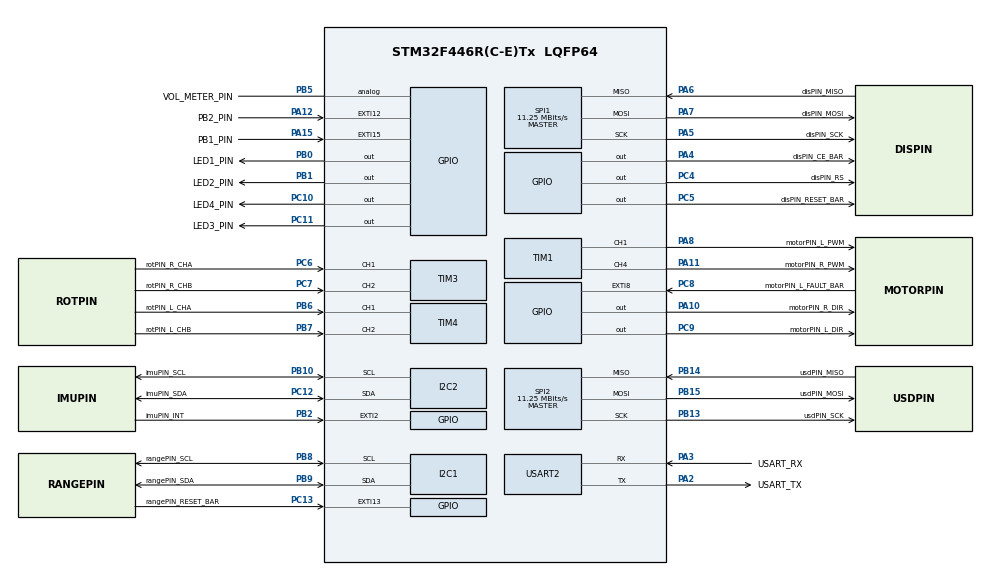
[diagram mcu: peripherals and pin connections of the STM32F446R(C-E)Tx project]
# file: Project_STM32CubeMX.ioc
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FREERTOS.Tasks01=defaultTask,0,128,StartDefaultTask
Mcu.Family=STM32F4
Mcu.Name=STM32F446R(C-E)Tx
Mcu.Package=LQFP64
NVIC.PriorityGroup=NVIC_PRIORITYGROUP_4
PA10.GPIO_Label=motorPIN_R_DIR
PA10.Signal=GPIO_Output
PA11.GPIO_Label=motorPIN_R_PWM
PA11.Signal=S_TIM1_CH4
PA12.GPIO_Label=PB2_PIN
PA12.Signal=GPXTI12
PA13.GPIO_Label=TMS
PA13.Mode=Trace-Asynchronous_SW
PA13.Signal=SYS_JTMS-SWDIO
PA14.GPIO_Label=TCK
PA14.Mode=Trace-Asynchronous_SW
PA14.Signal=SYS_JTCK-SWCLK
PA15.GPIO_Label=PB1_PIN
PA15.Signal=GPXTI15
PA2.GPIO_Label=USART_TX
PA2.Mode=Asynchronous
PA2.Signal=USART2_TX
PA3.GPIO_Label=USART_RX
PA3.Mode=Asynchronous
PA3.Signal=USART2_RX
PA4.GPIO_Label=disPIN_CE_BAR
PA4.Signal=GPIO_Output
PA5.GPIO_Label=disPIN_SCK
PA5.Mode=Full_Duplex_Master
PA5.Signal=SPI1_SCK
PA6.GPIO_Label=disPIN_MISO
PA6.Mode=Full_Duplex_Master
PA6.Signal=SPI1_MISO
PA7.GPIO_Label=disPIN_MOSI
PA7.Mode=Full_Duplex_Master
PA7.Signal=SPI1_MOSI
PA8.GPIO_Label=motorPIN_L_PWM
PA8.Signal=S_TIM1_CH1
PA9.GPIO_Label=motorPIN_R_FAULT_BAR
PA9.Signal=S_TIM1_CH2
PB0.GPIO_Label=LED1_PIN
PB0.Signal=GPIO_Output
PB1.GPIO_Label=LED2_PIN
PB1.Signal=GPIO_Output
PB10.GPIO_Label=imuPIN_SCL
PB10.Mode=I2C
PB10.Signal=I2C2_SCL
PB12.GPIO_Label=usdPIN_SS_BAR
PB12.Signal=SPI2_NSS
PB13.GPIO_Label=usdPIN_SCK
PB13.Mode=Full_Duplex_Master
PB13.Signal=SPI2_SCK
PB14.GPIO_Label=usdPIN_MISO
PB14.Mode=Full_Duplex_Master
PB14.Signal=SPI2_MISO
PB15.GPIO_Label=usdPIN_MOSI
PB15.Mode=Full_Duplex_Master
PB15.Signal=SPI2_MOSI
PB2.GPIO_Label=imuPIN_INT
PB2.Signal=GPXTI2
PB3.GPIO_Label=SWO
PB3.Mode=Trace-Asynchronous_SW
PB3.Signal=SYS_JTDO-SWO
PB5.GPIO_Label=VOL_METER_PIN
PB5.Signal=GPIO_Analog
PB6.GPIO_Label=rotPIN_L_CHA
PB6.Signal=S_TIM4_CH1
PB7.GPIO_Label=rotPIN_L_CHB
PB7.Signal=S_TIM4_CH2
PB8.GPIO_Label=rangePIN_SCL
PB8.Mode=I2C
PB8.Signal=I2C1_SCL
PB9.GPIO_Label=rangePIN_SDA
PB9.Mode=I2C
PB9.Signal=I2C1_SDA
PC10.GPIO_Label=LED4_PIN
PC10.Signal=GPIO_Output
PC11.GPIO_Label=LED3_PIN
PC11.Signal=GPIO_Output
PC12.GPIO_Label=imuPIN_SDA
PC12.Mode=I2C
PC12.Signal=I2C2_SDA
PC13.GPIO_Label=rangePIN_RESET_BAR
PC13.GPIO_ModeDefaultEXTI=GPIO_MODE_EVT_RISING
PC13.Signal=GPXTI13
PC14-OSC32_IN.Signal=RCC_OSC32_IN
PC15-OSC32_OUT.Signal=RCC_OSC32_OUT
PC4.GPIO_Label=disPIN_RS
PC4.Signal=GPIO_Output
PC5.GPIO_Label=disPIN_RESET_BAR
PC5.Signal=GPIO_Output
PC6.GPIO_Label=rotPIN_R_CHA
PC6.Signal=S_TIM3_CH1
PC7.GPIO_Label=rotPIN_R_CHB
PC7.Signal=S_TIM3_CH2
PC8.GPIO_Label=motorPIN_L_FAULT_BAR
PC8.Signal=GPXTI8
PC9.GPIO_Label=motorPIN_L_DIR
PC9.Signal=GPIO_Output
PH0-OSC_IN.Signal=RCC_OSC_IN
PH1-OSC_OUT.Signal=RCC_OSC_OUT
ProjectManager.HeapSize=0x200
ProjectManager.StackSize=0x400
ProjectManager.TargetToolchain=TrueSTUDIO
RCC.AHBFreq_Value=90000000
RCC.APB1CLKDivider=RCC_HCLK_DIV4
RCC.APB1Freq_Value=22500000
RCC.APB1TimFreq_Value=45000000
RCC.APB2CLKDivider=RCC_HCLK_DIV4
RCC.APB2Freq_Value=22500000
RCC.APB2TimFreq_Value=45000000
RCC.CortexFreq_Value=90000000
RCC.FLatency-AdvancedSettings=FLASH_LATENCY_2
RCC.HCLKFreq_Value=90000000
RCC.HSE_VALUE=8000000
RCC.HSI_VALUE=16000000
RCC.LSE_VALUE=32768
RCC.PLLN=360
RCC.PLLP=RCC_PLLP_DIV4
RCC.PWREXT_OverDrive=PWREXT_OverDrive_ACTIVATED
RCC.PWR_Regulator_Voltage_Scale=PWR_REGULATOR_VOLTAGE_SCALE1
RCC.SYSCLKFreq_VALUE=90000000
RCC.SYSCLKSource=RCC_SYSCLKSOURCE_PLLCLK
RCC.USBFreq_Value=180000000
RCC.VCOOutputFreq_Value=360000000
SH.S_TIM1_CH1.0=TIM1_CH1,PWM Generation1 CH1
SH.S_TIM1_CH2.0=TIM1_CH2
SH.S_TIM1_CH4.0=TIM1_CH4,PWM Generation4 CH4
SH.S_TIM3_CH1.0=TIM3_CH1,Input_Capture1_from_TI1
SH.S_TIM3_CH2.0=TIM3_CH2,Input_Capture2_from_TI2
SH.S_TIM4_CH1.0=TIM4_CH1,Input_Capture1_from_TI1
SH.S_TIM4_CH2.0=TIM4_CH2,Input_Capture2_from_TI2
SPI1.CalculateBaudRate=11.25 MBits/s
SPI1.Mode=SPI_MODE_MASTER
SPI2.CalculateBaudRate=11.25 MBits/s
SPI2.Mode=SPI_MODE_MASTER
SPI2.VirtualNSS=VM_NSSHARD
TIM1.Channel-PWM\ Generation4\ CH4=TIM_CHANNEL_4
TIM3.Channel-Input_Capture2_from_TI2=TIM_CHANNEL_2
TIM4.Channel-Input_Capture2_from_TI2=TIM_CHANNEL_2
VP_FATFS_VS_Generic.Mode=User_defined
VP_FREERTOS_VS_ENABLE.Mode=Enabled
VP_TIM3_VS_ClockSourceINT.Mode=Internal
board=NUCLEO-F446RE

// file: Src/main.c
/**
  ******************************************************************************
  * File Name          : main.c
  * Description        : Main program body
  ******************************************************************************
  *
  * COPYRIGHT(c) 2016 STMicroelectronics
  *
  * Redistribution and use in source and binary forms, with or without modification,
  * are permitted provided that the following conditions are met:
  *   1. Redistributions of source code must retain the above copyright notice,
  *      this list of conditions and the following disclaimer.
  *   2. Redistributions in binary form must reproduce the above copyright notice,
  *      this list of conditions and the following disclaimer in the documentation
  *      and/or other materials provided with the distribution.
  *   3. Neither the name of STMicroelectronics nor the names of its contributors
  *      may be used to endorse or promote products derived from this software
  *      without specific prior written permission.
  *
  * THIS SOFTWARE IS PROVIDED BY THE COPYRIGHT HOLDERS AND CONTRIBUTORS "AS IS"
  * AND ANY EXPRESS OR IMPLIED WARRANTIES, INCLUDING, BUT NOT LIMITED TO, THE
  * IMPLIED WARRANTIES OF MERCHANTABILITY AND FITNESS FOR A PARTICULAR PURPOSE ARE
  * DISCLAIMED. IN NO EVENT SHALL THE COPYRIGHT HOLDER OR CONTRIBUTORS BE LIABLE
  * FOR ANY DIRECT, INDIRECT, INCIDENTAL, SPECIAL, EXEMPLARY, OR CONSEQUENTIAL
  * DAMAGES (INCLUDING, BUT NOT LIMITED TO, PROCUREMENT OF SUBSTITUTE GOODS OR
  * SERVICES; LOSS OF USE, DATA, OR PROFITS; OR BUSINESS INTERRUPTION) HOWEVER
  * CAUSED AND ON ANY THEORY OF LIABILITY, WHETHER IN CONTRACT, STRICT LIABILITY,
  * OR TORT (INCLUDING NEGLIGENCE OR OTHERWISE) ARISING IN ANY WAY OUT OF THE USE
  * OF THIS SOFTWARE, EVEN IF ADVISED OF THE POSSIBILITY OF SUCH DAMAGE.
  *
  ******************************************************************************
  */
#include "stm32f4xx_hal.h"
#include "cmsis_os.h"
#include "fatfs.h"

I2C_HandleTypeDef hi2c1;
I2C_HandleTypeDef hi2c2;

SPI_HandleTypeDef hspi1;
SPI_HandleTypeDef hspi2;

TIM_HandleTypeDef htim1;
TIM_HandleTypeDef htim3;
TIM_HandleTypeDef htim4;

UART_HandleTypeDef huart2;

osThreadId defaultTaskHandle;

/* USER CODE BEGIN PV */
/* Private variables ---------------------------------------------------------*/

/* USER CODE END PV */

void SystemClock_Config(void);
static void MX_GPIO_Init(void);
static void MX_I2C1_Init(void);
static void MX_I2C2_Init(void);
static void MX_SPI1_Init(void);
static void MX_SPI2_Init(void);
static void MX_TIM1_Init(void);
static void MX_TIM3_Init(void);
static void MX_TIM4_Init(void);
static void MX_USART2_UART_Init(void);
void StartDefaultTask(void const * argument);

void HAL_TIM_MspPostInit(TIM_HandleTypeDef *htim);

/* USER CODE BEGIN PFP */
/* Private function prototypes -----------------------------------------------*/

/* USER CODE END PFP */

int main(void)
{

  /* MCU Configuration----------------------------------------------------------*/

  /* Reset of all peripherals, Initializes the Flash interface and the Systick. */
  HAL_Init();

  /* Configure the system clock */
  SystemClock_Config();

  /* Initialize all configured peripherals */
  MX_GPIO_Init();
  MX_I2C1_Init();
  MX_I2C2_Init();
  MX_SPI1_Init();
  MX_SPI2_Init();
  MX_TIM1_Init();
  MX_TIM3_Init();
  MX_TIM4_Init();
  MX_USART2_UART_Init();

  /* Create the thread(s) */
  /* definition and creation of defaultTask */
  osThreadDef(defaultTask, StartDefaultTask, osPriorityNormal, 0, 128);
  defaultTaskHandle = osThreadCreate(osThread(defaultTask), NULL);

  /* Start scheduler */
  osKernelStart();

  /* We should never get here as control is now taken by the scheduler */

  /* Infinite loop */
  while (1)
  {

  }

}

/** System Clock Configuration
*/
void SystemClock_Config(void)
{

  RCC_OscInitTypeDef RCC_OscInitStruct;
  RCC_ClkInitTypeDef RCC_ClkInitStruct;

  __HAL_RCC_PWR_CLK_ENABLE();

  __HAL_PWR_VOLTAGESCALING_CONFIG(PWR_REGULATOR_VOLTAGE_SCALE1);

  RCC_OscInitStruct.OscillatorType = RCC_OSCILLATORTYPE_HSI;
  RCC_OscInitStruct.HSIState = RCC_HSI_ON;
  RCC_OscInitStruct.HSICalibrationValue = 16;
  RCC_OscInitStruct.PLL.PLLState = RCC_PLL_ON;
  RCC_OscInitStruct.PLL.PLLSource = RCC_PLLSOURCE_HSI;
  RCC_OscInitStruct.PLL.PLLM = 16;
  RCC_OscInitStruct.PLL.PLLN = 360;
  RCC_OscInitStruct.PLL.PLLP = RCC_PLLP_DIV2;
  RCC_OscInitStruct.PLL.PLLQ = 2;
  RCC_OscInitStruct.PLL.PLLR = 2;
  HAL_RCC_OscConfig(&RCC_OscInitStruct);

  HAL_PWREx_EnableOverDrive();

  RCC_ClkInitStruct.ClockType = RCC_CLOCKTYPE_HCLK|RCC_CLOCKTYPE_SYSCLK
                              |RCC_CLOCKTYPE_PCLK1|RCC_CLOCKTYPE_PCLK2;
  RCC_ClkInitStruct.SYSCLKSource = RCC_SYSCLKSOURCE_PLLCLK;
  RCC_ClkInitStruct.AHBCLKDivider = RCC_SYSCLK_DIV1;
  RCC_ClkInitStruct.APB1CLKDivider = RCC_HCLK_DIV4;
  RCC_ClkInitStruct.APB2CLKDivider = RCC_HCLK_DIV4;
  HAL_RCC_ClockConfig(&RCC_ClkInitStruct, FLASH_LATENCY_5);

  HAL_SYSTICK_Config(HAL_RCC_GetHCLKFreq()/1000);

  HAL_SYSTICK_CLKSourceConfig(SYSTICK_CLKSOURCE_HCLK);

  /* SysTick_IRQn interrupt configuration */
  HAL_NVIC_SetPriority(SysTick_IRQn, 15, 0);
}

/* I2C1 init function */
void MX_I2C1_Init(void)
{

  hi2c1.Instance = I2C1;
  hi2c1.Init.ClockSpeed = 100000;
  hi2c1.Init.DutyCycle = I2C_DUTYCYCLE_2;
  hi2c1.Init.OwnAddress1 = 0;
  hi2c1.Init.AddressingMode = I2C_ADDRESSINGMODE_7BIT;
  hi2c1.Init.DualAddressMode = I2C_DUALADDRESS_DISABLE;
  hi2c1.Init.OwnAddress2 = 0;
  hi2c1.Init.GeneralCallMode = I2C_GENERALCALL_DISABLE;
  hi2c1.Init.NoStretchMode = I2C_NOSTRETCH_DISABLE;
  HAL_I2C_Init(&hi2c1);

}

/* I2C2 init function */
void MX_I2C2_Init(void)
{

  hi2c2.Instance = I2C2;
  hi2c2.Init.ClockSpeed = 100000;
  hi2c2.Init.DutyCycle = I2C_DUTYCYCLE_2;
  hi2c2.Init.OwnAddress1 = 0;
  hi2c2.Init.AddressingMode = I2C_ADDRESSINGMODE_7BIT;
  hi2c2.Init.DualAddressMode = I2C_DUALADDRESS_DISABLE;
  hi2c2.Init.OwnAddress2 = 0;
  hi2c2.Init.GeneralCallMode = I2C_GENERALCALL_DISABLE;
  hi2c2.Init.NoStretchMode = I2C_NOSTRETCH_DISABLE;
  HAL_I2C_Init(&hi2c2);

}

/* SPI1 init function */
void MX_SPI1_Init(void)
{

  hspi1.Instance = SPI1;
  hspi1.Init.Mode = SPI_MODE_MASTER;
  hspi1.Init.Direction = SPI_DIRECTION_2LINES;
  hspi1.Init.DataSize = SPI_DATASIZE_8BIT;
  hspi1.Init.CLKPolarity = SPI_POLARITY_LOW;
  hspi1.Init.CLKPhase = SPI_PHASE_1EDGE;
  hspi1.Init.NSS = SPI_NSS_SOFT;
  hspi1.Init.BaudRatePrescaler = SPI_BAUDRATEPRESCALER_2;
  hspi1.Init.FirstBit = SPI_FIRSTBIT_MSB;
  hspi1.Init.TIMode = SPI_TIMODE_DISABLE;
  hspi1.Init.CRCCalculation = SPI_CRCCALCULATION_DISABLE;
  hspi1.Init.CRCPolynomial = 10;
  HAL_SPI_Init(&hspi1);

}

/* SPI2 init function */
void MX_SPI2_Init(void)
{

  hspi2.Instance = SPI2;
  hspi2.Init.Mode = SPI_MODE_MASTER;
  hspi2.Init.Direction = SPI_DIRECTION_2LINES;
  hspi2.Init.DataSize = SPI_DATASIZE_8BIT;
  hspi2.Init.CLKPolarity = SPI_POLARITY_LOW;
  hspi2.Init.CLKPhase = SPI_PHASE_1EDGE;
  hspi2.Init.NSS = SPI_NSS_SOFT;
  hspi2.Init.BaudRatePrescaler = SPI_BAUDRATEPRESCALER_2;
  hspi2.Init.FirstBit = SPI_FIRSTBIT_MSB;
  hspi2.Init.TIMode = SPI_TIMODE_DISABLE;
  hspi2.Init.CRCCalculation = SPI_CRCCALCULATION_DISABLE;
  hspi2.Init.CRCPolynomial = 10;
  HAL_SPI_Init(&hspi2);

}

/* TIM1 init function */
void MX_TIM1_Init(void)
{

  TIM_MasterConfigTypeDef sMasterConfig;
  TIM_BreakDeadTimeConfigTypeDef sBreakDeadTimeConfig;
  TIM_OC_InitTypeDef sConfigOC;

  htim1.Instance = TIM1;
  htim1.Init.Prescaler = 0;
  htim1.Init.CounterMode = TIM_COUNTERMODE_UP;
  htim1.Init.Period = 0;
  htim1.Init.ClockDivision = TIM_CLOCKDIVISION_DIV1;
  htim1.Init.RepetitionCounter = 0;
  HAL_TIM_PWM_Init(&htim1);

  sMasterConfig.MasterOutputTrigger = TIM_TRGO_RESET;
  sMasterConfig.MasterSlaveMode = TIM_MASTERSLAVEMODE_DISABLE;
  HAL_TIMEx_MasterConfigSynchronization(&htim1, &sMasterConfig);

  sBreakDeadTimeConfig.OffStateRunMode = TIM_OSSR_DISABLE;
  sBreakDeadTimeConfig.OffStateIDLEMode = TIM_OSSI_DISABLE;
  sBreakDeadTimeConfig.LockLevel = TIM_LOCKLEVEL_OFF;
  sBreakDeadTimeConfig.DeadTime = 0;
  sBreakDeadTimeConfig.BreakState = TIM_BREAK_DISABLE;
  sBreakDeadTimeConfig.BreakPolarity = TIM_BREAKPOLARITY_HIGH;
  sBreakDeadTimeConfig.AutomaticOutput = TIM_AUTOMATICOUTPUT_DISABLE;
  HAL_TIMEx_ConfigBreakDeadTime(&htim1, &sBreakDeadTimeConfig);

  sConfigOC.OCMode = TIM_OCMODE_PWM1;
  sConfigOC.Pulse = 0;
  sConfigOC.OCPolarity = TIM_OCPOLARITY_HIGH;
  sConfigOC.OCNPolarity = TIM_OCNPOLARITY_HIGH;
  sConfigOC.OCFastMode = TIM_OCFAST_DISABLE;
  sConfigOC.OCIdleState = TIM_OCIDLESTATE_RESET;
  sConfigOC.OCNIdleState = TIM_OCNIDLESTATE_RESET;
  HAL_TIM_PWM_ConfigChannel(&htim1, &sConfigOC, TIM_CHANNEL_1);

  HAL_TIM_PWM_ConfigChannel(&htim1, &sConfigOC, TIM_CHANNEL_4);

  HAL_TIM_MspPostInit(&htim1);

}

/* TIM3 init function */
void MX_TIM3_Init(void)
{

  TIM_ClockConfigTypeDef sClockSourceConfig;
  TIM_MasterConfigTypeDef sMasterConfig;
  TIM_IC_InitTypeDef sConfigIC;

  htim3.Instance = TIM3;
  htim3.Init.Prescaler = 0;
  htim3.Init.CounterMode = TIM_COUNTERMODE_UP;
  htim3.Init.Period = 0;
  htim3.Init.ClockDivision = TIM_CLOCKDIVISION_DIV1;
  HAL_TIM_Base_Init(&htim3);

  sClockSourceConfig.ClockSource = TIM_CLOCKSOURCE_INTERNAL;
  HAL_TIM_ConfigClockSource(&htim3, &sClockSourceConfig);

  HAL_TIM_IC_Init(&htim3);

  sMasterConfig.MasterOutputTrigger = TIM_TRGO_RESET;
  sMasterConfig.MasterSlaveMode = TIM_MASTERSLAVEMODE_DISABLE;
  HAL_TIMEx_MasterConfigSynchronization(&htim3, &sMasterConfig);

  sConfigIC.ICPolarity = TIM_INPUTCHANNELPOLARITY_RISING;
  sConfigIC.ICSelection = TIM_ICSELECTION_DIRECTTI;
  sConfigIC.ICPrescaler = TIM_ICPSC_DIV1;
  sConfigIC.ICFilter = 0;
  HAL_TIM_IC_ConfigChannel(&htim3, &sConfigIC, TIM_CHANNEL_1);

  HAL_TIM_IC_ConfigChannel(&htim3, &sConfigIC, TIM_CHANNEL_2);

}

/* TIM4 init function */
void MX_TIM4_Init(void)
{

  TIM_MasterConfigTypeDef sMasterConfig;
  TIM_IC_InitTypeDef sConfigIC;

  htim4.Instance = TIM4;
  htim4.Init.Prescaler = 0;
  htim4.Init.CounterMode = TIM_COUNTERMODE_UP;
  htim4.Init.Period = 0;
  htim4.Init.ClockDivision = TIM_CLOCKDIVISION_DIV1;
  HAL_TIM_IC_Init(&htim4);

  sMasterConfig.MasterOutputTrigger = TIM_TRGO_RESET;
  sMasterConfig.MasterSlaveMode = TIM_MASTERSLAVEMODE_DISABLE;
  HAL_TIMEx_MasterConfigSynchronization(&htim4, &sMasterConfig);

  sConfigIC.ICPolarity = TIM_INPUTCHANNELPOLARITY_RISING;
  sConfigIC.ICSelection = TIM_ICSELECTION_DIRECTTI;
  sConfigIC.ICPrescaler = TIM_ICPSC_DIV1;
  sConfigIC.ICFilter = 0;
  HAL_TIM_IC_ConfigChannel(&htim4, &sConfigIC, TIM_CHANNEL_1);

  HAL_TIM_IC_ConfigChannel(&htim4, &sConfigIC, TIM_CHANNEL_2);

}

/* USART2 init function */
void MX_USART2_UART_Init(void)
{

  huart2.Instance = USART2;
  huart2.Init.BaudRate = 115200;
  huart2.Init.WordLength = UART_WORDLENGTH_8B;
  huart2.Init.StopBits = UART_STOPBITS_1;
  huart2.Init.Parity = UART_PARITY_NONE;
  huart2.Init.Mode = UART_MODE_TX_RX;
  huart2.Init.HwFlowCtl = UART_HWCONTROL_NONE;
  huart2.Init.OverSampling = UART_OVERSAMPLING_16;
  HAL_UART_Init(&huart2);

}

/** Configure pins as
        * Analog
        * Input
        * Output
        * EVENT_OUT
        * EXTI
*/
void MX_GPIO_Init(void)
{

  GPIO_InitTypeDef GPIO_InitStruct;

  /* GPIO Ports Clock Enable */
  __HAL_RCC_GPIOC_CLK_ENABLE();
  __HAL_RCC_GPIOH_CLK_ENABLE();
  __HAL_RCC_GPIOA_CLK_ENABLE();
  __HAL_RCC_GPIOB_CLK_ENABLE();

  /*Configure GPIO pin : rangePIN_RESET_BAR_Pin */
  GPIO_InitStruct.Pin = rangePIN_RESET_BAR_Pin;
  GPIO_InitStruct.Mode = GPIO_MODE_EVT_RISING;
  GPIO_InitStruct.Pull = GPIO_NOPULL;
  HAL_GPIO_Init(rangePIN_RESET_BAR_GPIO_Port, &GPIO_InitStruct);

  /*Configure GPIO pins : disPIN_CE_BAR_Pin motorPIN_R_DIR_Pin */
  GPIO_InitStruct.Pin = disPIN_CE_BAR_Pin|motorPIN_R_DIR_Pin;
  GPIO_InitStruct.Mode = GPIO_MODE_OUTPUT_PP;
  GPIO_InitStruct.Pull = GPIO_NOPULL;
  GPIO_InitStruct.Speed = GPIO_SPEED_FREQ_LOW;
  HAL_GPIO_Init(GPIOA, &GPIO_InitStruct);

  /*Configure GPIO pins : disPIN_RS_Pin disPIN_RESET_BAR_Pin motorPIN_L_DIR_Pin LED4_PIN_Pin
                           LED3_PIN_Pin */
  GPIO_InitStruct.Pin = disPIN_RS_Pin|disPIN_RESET_BAR_Pin|motorPIN_L_DIR_Pin|LED4_PIN_Pin
                          |LED3_PIN_Pin;
  GPIO_InitStruct.Mode = GPIO_MODE_OUTPUT_PP;
  GPIO_InitStruct.Pull = GPIO_NOPULL;
  GPIO_InitStruct.Speed = GPIO_SPEED_FREQ_LOW;
  HAL_GPIO_Init(GPIOC, &GPIO_InitStruct);

  /*Configure GPIO pins : LED1_PIN_Pin LED2_PIN_Pin */
  GPIO_InitStruct.Pin = LED1_PIN_Pin|LED2_PIN_Pin;
  GPIO_InitStruct.Mode = GPIO_MODE_OUTPUT_PP;
  GPIO_InitStruct.Pull = GPIO_NOPULL;
  GPIO_InitStruct.Speed = GPIO_SPEED_FREQ_LOW;
  HAL_GPIO_Init(GPIOB, &GPIO_InitStruct);

  /*Configure GPIO pin : imuPIN_INT_Pin */
  GPIO_InitStruct.Pin = imuPIN_INT_Pin;
  GPIO_InitStruct.Mode = GPIO_MODE_IT_RISING;
  GPIO_InitStruct.Pull = GPIO_NOPULL;
  HAL_GPIO_Init(imuPIN_INT_GPIO_Port, &GPIO_InitStruct);

  /*Configure GPIO pin : motorPIN_L_FAULT_BAR_Pin */
  GPIO_InitStruct.Pin = motorPIN_L_FAULT_BAR_Pin;
  GPIO_InitStruct.Mode = GPIO_MODE_IT_RISING;
  GPIO_InitStruct.Pull = GPIO_NOPULL;
  HAL_GPIO_Init(motorPIN_L_FAULT_BAR_GPIO_Port, &GPIO_InitStruct);

  /*Configure GPIO pins : PB2_PIN_Pin PB1_PIN_Pin */
  GPIO_InitStruct.Pin = PB2_PIN_Pin|PB1_PIN_Pin;
  GPIO_InitStruct.Mode = GPIO_MODE_IT_RISING;
  GPIO_InitStruct.Pull = GPIO_NOPULL;
  HAL_GPIO_Init(GPIOA, &GPIO_InitStruct);

  /*Configure GPIO pin : VOL_METER_PIN_Pin */
  GPIO_InitStruct.Pin = VOL_METER_PIN_Pin;
  GPIO_InitStruct.Mode = GPIO_MODE_ANALOG;
  GPIO_InitStruct.Pull = GPIO_NOPULL;
  HAL_GPIO_Init(VOL_METER_PIN_GPIO_Port, &GPIO_InitStruct);

  /*Configure GPIO pin Output Level */
  HAL_GPIO_WritePin(GPIOA, disPIN_CE_BAR_Pin|motorPIN_R_DIR_Pin, GPIO_PIN_RESET);

  /*Configure GPIO pin Output Level */
  HAL_GPIO_WritePin(GPIOC, disPIN_RS_Pin|disPIN_RESET_BAR_Pin|motorPIN_L_DIR_Pin|LED4_PIN_Pin
                          |LED3_PIN_Pin, GPIO_PIN_RESET);

  /*Configure GPIO pin Output Level */
  HAL_GPIO_WritePin(GPIOB, LED1_PIN_Pin|LED2_PIN_Pin, GPIO_PIN_RESET);

}

/* StartDefaultTask function */
void StartDefaultTask(void const * argument)
{
  /* init code for FATFS */
  MX_FATFS_Init();

  for(;;)
  {
    osDelay(1);
  }
}

/************************ (C) COPYRIGHT STMicroelectronics *****END OF FILE****/
